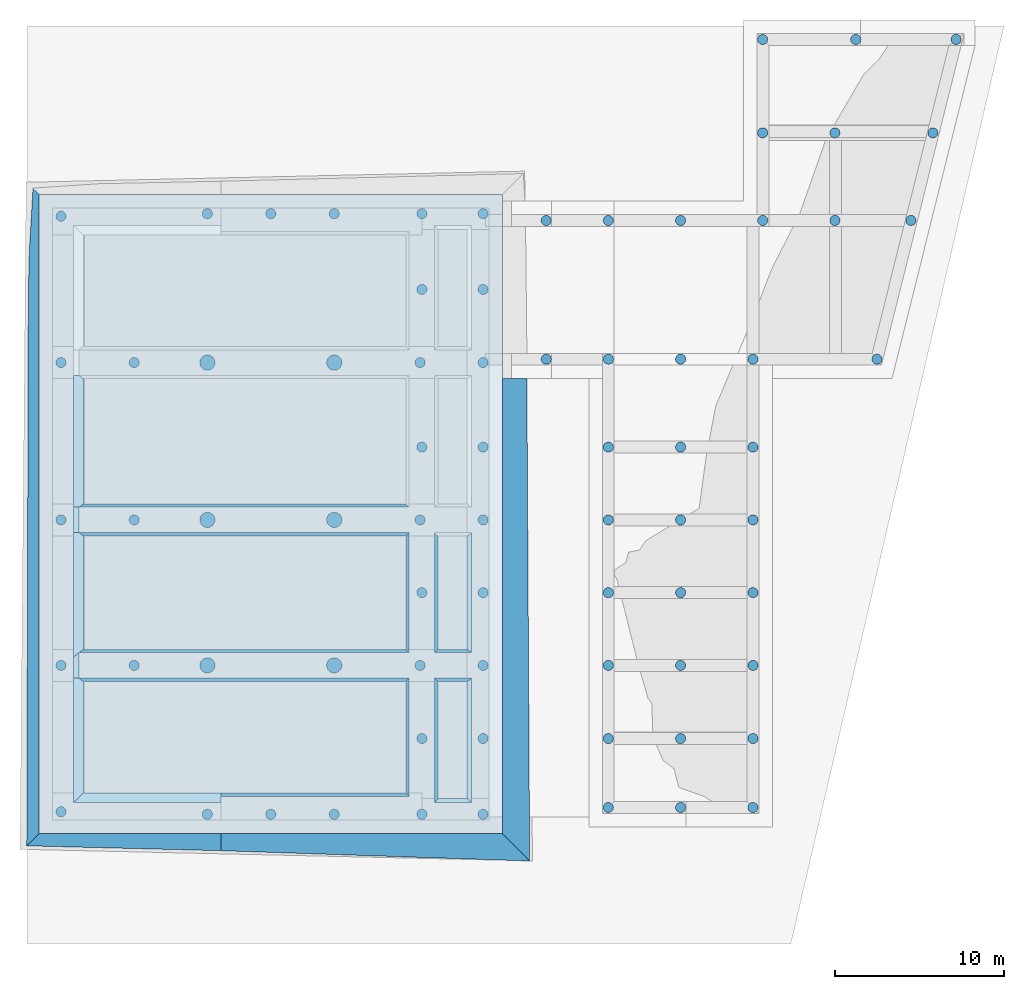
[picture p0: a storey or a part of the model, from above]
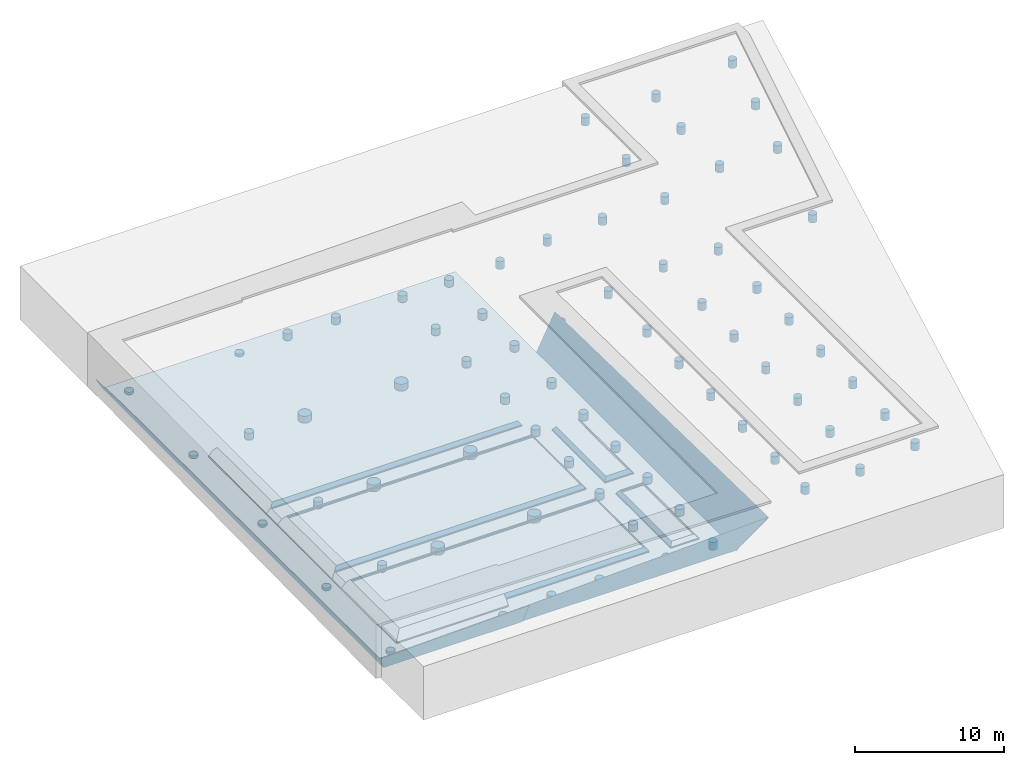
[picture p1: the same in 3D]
Properties of the parts of a building model (IFC2X3)

# File
Description: ViewDefinition [CoordinationView_V2.0, QuantityTakeOffAddOnView, SpaceBoundary2ndLevelAddOnView], Option [Elements to export: Entire project], Option [Partial Structure Display: Entire Model], Option [IFC Domain: All], Option [Structural Function: All Elements], Option [Convert Grid elements: On], Option [Convert IFC Annotations and ARCHICAD 2D elements: Off], Option [Convert 2D symbols of Doors and Windows: Off], Option [Export geometries that Participates in Collision Detection only: Off], Option [Split complex elements: Off], Option [Material Preservation: Explode where necessary], Option [Elements in Solid Element Operations: Extruded/revolved], Option [Elements with junctions: Extruded/revolved without junctions], Option [IFC Model position: Survey Point and Project Origin], Option [Curtain Wall export mode: Container Element], Option [Railing export mode: Single Element], Option [Stair export mode: Container Element], Option [Properties To Export: All properties], Option [Space containment: On], Option [IFC Domain For Space Containment: All], Option [Bounding Box: Off], Option [Geometry to type objects: Off], Option [Element Properties: Off], Option [Building Material Properties: Off], Option [Element Parameters: Off], Option [Component Parameters: Off], Option [IFC Base Quantities: On], Option [Door Window Parameters: On], Option [IFC Space boundaries: On], Option [ARCHICAD Zone Categories as IFC Space classification data: Off], Option [Element Classifications: Off]
File name: C:\Users\QGPC4\Desktop\VV Přelouč - Výkopy 3D model.ifc
Time: 2024-04-22T10:31:03
Author: Architect
Organization: Building Designer Office
Written by: The EXPRESS Data Manager Version 5.02.0100.09 : 26 Sep 2013
Made in: IFC file generated by GRAPHISOFT ARCHICAD 25.0.0 CZE FULL Windows version (IFC add-on version: 4013 CZE FULL).
Authorization: The authorising person

# IfcSite, Exteriér
RefLatitude: 50, 5, 0, 0; RefLongitude: 14, 25, 0, 0; RefElevation: 180000 mm
BaseQuantities - GrossPerimeter: 0 mm; GrossArea: 0 m2

# IfcBuilding, Budova
BaseQuantities - GrossFloorArea: 0 m2

# IfcBuildingStorey (5)
In: Budova
BaseQuantities - GrossFloorArea: 0 m2
Name | Elevation (mm) | NetHeight (mm) = GrossHeight (mm) = Height (mm)
Základy | -5000 | 1900
1.PP | -3100 | 3100
1.NP | 0 | 2950
Střecha - světlíky | 2950 | 6000
Střecha pohled | 8950 | 6000

# IfcBuildingElementProxy: Beton Prostý C 16/20 100 (36)
In: Základy
Material: Beton Prostý C 16/20
AC_Pset_RenovationAndPhasing - Renovation Status: Existing

# IfcBuildingElementProxy: Nástěnný hydrant 25, Ž01
In: 1.PP
AC_Pset_RenovationAndPhasing - Renovation Status: New

# IfcColumn: Železobeton C 20/25 D600 (67)
In: Základy
Type - PredefinedType: COLUMN
Material: Železobeton C 20/25
AC_Pset_RenovationAndPhasing - Renovation Status: Existing
Pset_ColumnCommon - LoadBearing: yes; Reference: Železobeton C 20/25 D600
BaseQuantities - Length: 650 mm; Width: 600 mm; Depth: 600 mm; CrossSectionArea: 0.282743 m2; OuterSurfaceArea: 1.22396 m2; TotalSurfaceArea: 1.78713 m2; GrossSurfaceArea: 1.78713 m2; GrossVolume: 0.183028 m3; NetVolume: 0.183028 m3

# IfcColumn: Železobeton C 20/25 D900 (6)
In: Základy
Type - PredefinedType: COLUMN
Material: Železobeton C 20/25
AC_Pset_RenovationAndPhasing - Renovation Status: Existing
Pset_ColumnCommon - LoadBearing: yes; Reference: Železobeton C 20/25 D900
BaseQuantities - Length: 650 mm; Width: 900 mm; Depth: 900 mm; CrossSectionArea: 0.636173 m2; OuterSurfaceArea: 1.83652 m2; TotalSurfaceArea: 3.10523 m2; GrossSurfaceArea: 3.10523 m2; GrossVolume: 0.412332 m3; NetVolume: 0.412332 m3

# IfcCovering: Zemina - původní 4395, Vytěžená zemina
In: Základy
Type - PredefinedType: CEILING
Material: Zemina - původní
Pset_CoveringCommon - Material: Zemina - původní
AC_Pset_RenovationAndPhasing - Renovation Status: Existing
BaseQuantities - GrossArea: 23.6487 m2; NetArea: 23.6487 m2

# IfcSlab: Beton Prostý C 16/20 58 (26)
In: Základy
Type - PredefinedType: ROOF
Material: Beton Prostý C 16/20 58.3966 mm
AC_Pset_RenovationAndPhasing - Renovation Status: Existing
Pset_SlabCommon - LoadBearing: yes
BaseQuantities - Width: 58.3966 mm
Name | Perimeter (mm) | GrossArea (m2) = NetArea (m2) | GrossVolume (m3) = NetVolume (m3)
6 x Podkladní beton | 4730.63 | 0.669559 | 0.0391
3 x Podkladní beton | 39400.8 | 6.60656 | 0.385801
2 x Podkladní beton | 15993.2 | 2.60289 | 0.152
2 x Podkladní beton | 15090.6 | 2.44363 | 0.1427
Podkladní beton | 14648 | 2.57975 | 0.150649
3 x Podkladní beton | 39398.9 | 6.58411 | 0.38449
2 x Podkladní beton | 22767.4 | 3.75974 | 0.219556
Podkladní beton | 4783.77 | 0.73093 | 0.0426839
2 x Podkladní beton | 14593.2 | 2.36315 | 0.138
2 x Podkladní beton | 15143.8 | 2.66761 | 0.15578
2 x Podkladní beton | 14383.2 | 2.32719 | 0.1359

# IfcSlab: Beton Prostý C 16/20 60, Podkladní beton
In: Základy
Type - PredefinedType: ROOF
Material: Beton Prostý C 16/20 60.0958 mm
AC_Pset_RenovationAndPhasing - Renovation Status: Existing
Pset_SlabCommon - LoadBearing: yes
BaseQuantities - Width: 60.0958 mm; Perimeter: 4783.77 mm; GrossArea: 0.73093 m2; NetArea: 0.73093 m2; GrossVolume: 0.0439258 m3; NetVolume: 0.0439258 m3

# IfcSlab: Beton Prostý C 16/20 67 (10)
In: Základy
Type - PredefinedType: ROOF
AC_Pset_RenovationAndPhasing - Renovation Status: Existing
Pset_SlabCommon - LoadBearing: yes
Name | Material | Width (mm) | Perimeter (mm) | GrossArea (m2) = NetArea (m2) | GrossVolume (m3) = NetVolume (m3)
2 x Podkladní beton | Beton Prostý C 16/20 66.8834 mm | 66.8834 | 15866.2 | 5.94135 | 0.397378
2 x Podkladní beton | Beton Prostý C 16/20 66.8834 mm | 66.8834 | 3941.6 | 0.706203 | 0.0472333
Podkladní beton | Beton Prostý C 16/20 66.8669 mm | 66.8669 | 16048 | 2.84146 | 0.19
2 x Podkladní beton | Beton Prostý C 16/20 66.8834 mm | 66.8834 | 18725.5 | 7.12317 | 0.476422
Podkladní beton | Beton Prostý C 16/20 66.8834 mm | 66.8834 | 16989.8 | 6.51429 | 0.435698
Podkladní beton | Beton Prostý C 16/20 66.8834 mm | 66.8834 | 3752.91 | 0.64693 | 0.0432689
Podkladní beton | Beton Prostý C 16/20 66.8834 mm | 66.8834 | 15904.7 | 5.98224 | 0.400112

# IfcSlab: Hutněný násyp 150, Zásyp
In: 1.PP
Type - PredefinedType: FLOOR
Material: Hutněný násyp 150 mm
AC_Pset_RenovationAndPhasing - Renovation Status: Existing
Pset_SlabCommon - LoadBearing: yes
BaseQuantities - Width: 150 mm; Perimeter: 123480 mm; GrossArea: 0 m2; NetArea: 0 m2; GrossVolume: 0 m3; NetVolume: 0 m3

# IfcSlab: Hutněný násyp 1631, Zásyp
In: Základy
Type - PredefinedType: FLOOR
Material: Hutněný násyp 1631.38 mm
AC_Pset_RenovationAndPhasing - Renovation Status: Existing
Pset_SlabCommon - LoadBearing: yes
BaseQuantities - Width: 1631.38 mm; Perimeter: 83320 mm; GrossArea: 180.492 m2; NetArea: 180.492 m2; GrossVolume: 216.451 m3; NetVolume: 216.451 m3

# IfcSlab: Hutněný násyp 3590, Zásyp
In: Základy
Type - PredefinedType: FLOOR
Material: Hutněný násyp 3590 mm
AC_Pset_RenovationAndPhasing - Renovation Status: Existing
Pset_SlabCommon - LoadBearing: yes
BaseQuantities - Width: 3590 mm; Perimeter: 45535.8 mm; GrossArea: 114.391 m2; NetArea: 114.146 m2; GrossVolume: 411.399 m3; NetVolume: 410.517 m3

# IfcSlab: Hutněný násyp 4421, Zásyp
In: Základy
Type - PredefinedType: FLOOR
Material: Hutněný násyp 4421.18 mm
AC_Pset_RenovationAndPhasing - Renovation Status: Existing
Pset_SlabCommon - LoadBearing: yes
BaseQuantities - Width: 4421.18 mm; Perimeter: 263091 mm; GrossArea: 0 m2; NetArea: 0 m2; GrossVolume: 476.972 m3; NetVolume: 476.972 m3

# IfcSlab: Hutněný násyp 700 (11)
In: Základy
Type - PredefinedType: FLOOR
Material: Hutněný násyp 700 mm
AC_Pset_RenovationAndPhasing - Renovation Status: Existing
Pset_SlabCommon - LoadBearing: yes
BaseQuantities - Width: 700 mm
Name | Perimeter (mm) | GrossArea (m2) | NetArea (m2) | GrossVolume (m3) | NetVolume (m3)
Zásyp | 22500 | 12.4814 | 12.2852 | 2.25481 | 2.11744
Zásyp | 22900 | 7.29258 | 7.29258 | 0.57054 | 0.57054
Zásyp | 29727.8 | 25.4487 | 25.1651 | 5.4664 | 5.26789
Zásyp | 26654.7 | 15.9011 | 11.262 | 4.54066 | 1.29328
Zásyp | 22900 | 4.10036 | 4.10036 | 0.343008 | 0.343008
Zásyp | 24700 | 27.8245 | 27.8245 | 7.25127 | 7.25127
Zásyp | 20752.4 | 0 | 0 | 0 | 0
Zásyp | 30700 | 58.5365 | 58.5365 | 23.9905 | 23.9905
Zásyp | 22900 | 18.6996 | 18.6996 | 4.39526 | 4.39526
Zásyp | 23340 | 4.26716 | 4.26716 | 0.286414 | 0.286414
Zásyp | 22900 | 3.23502 | 3.23502 | 0.0932595 | 0.0932595

# IfcSlab: Hutněný násyp 728 (5)
In: Základy
Type - PredefinedType: FLOOR
Material: Hutněný násyp 728 mm
AC_Pset_RenovationAndPhasing - Renovation Status: Existing
Pset_SlabCommon - LoadBearing: yes
BaseQuantities - Width: 728 mm; NetArea: 0 m2
Name | Perimeter (mm) | GrossArea (m2) | GrossVolume (m3) | NetVolume (m3)
Zásyp | 19080 | 0 | 2.01844 | 2.01844
Zásyp | 19960 | 0 | 2.04646 | 2.04646
Zásyp | 223142 | 2.33127 | 27.8688 | 26.1716
Zásyp | 18560 | 0.391 | 2.23802 | 1.95337
Zásyp | 19080 | 0 | 2.01968 | 2.01968

# IfcSlab: Zemina - původní 0, Pomocné výkopy
In: Základy
Type - PredefinedType: ROOF
Material: Zemina - původní 0.45399 mm
AC_Pset_RenovationAndPhasing - Renovation Status: Existing
Pset_SlabCommon - LoadBearing: yes
BaseQuantities - Width: 0.45399 mm; Perimeter: 41026.9 mm; GrossArea: 49.7158 m2; NetArea: 49.7158 m2; GrossVolume: 0.0225705 m3; NetVolume: 0.0225705 m3

# IfcSlab: Zemina - původní 1 (32)
Type - PredefinedType: FLOOR
Material: Zemina - původní 1 mm
AC_Pset_RenovationAndPhasing - Renovation Status: Existing
Pset_SlabCommon - LoadBearing: yes
BaseQuantities - Width: 1 mm
Name | In | Perimeter (mm) | GrossArea (m2) | NetArea (m2) | GrossVolume (m3) | NetVolume (m3)
Pomocné výkopy | Základy | 22450 | 0 | 0 | 0 | 0
Pomocné výkopy | Základy | 16400 | 5.24999 | 5.24999 | 0.00524999 | 0.00524999
Pomocné výkopy | Základy | 41628.3 | 14.0722 | 13.7878 | 0.0140722 | 0.0137878
6 x Pomocné výkopy | Základy | 17100 | 5.495 | 5.21342 | 0.005495 | 0.00521342
Pomocné výkopy | Základy | 64806.1 | 46.3541 | 44.6646 | 0.0463541 | 0.0446646
Pomocné výkopy | Základy | 53528.7 | 37.8954 | 36.4886 | 0.0378954 | 0.0364886
3 x Pomocné výkopy | Základy | 22900 | 28.26 | 28.26 | 0.02826 | 0.02826
Pomocné výkopy | Základy | 9040.01 | 4.53002 | 4.53002 | 0.00453002 | 0.00453002
Pomocné výkopy | Základy | 10440 | 5.58 | 5.29842 | 0.00558 | 0.00529842
Pomocné výkopy | Základy | 7710.39 | 3.5328 | 3.25121 | 0.0035328 | 0.00325121
Pomocné výkopy | Základy | 29727.8 | 47.6959 | 47.4123 | 0.0476959 | 0.0474123
Pomocné výkopy | Základy | 7710.38 | 3.53278 | 3.2512 | 0.00353278 | 0.0032512
Pomocné výkopy | Základy | 67500 | 47.175 | 45.2039 | 0.047175 | 0.0452039
Pomocné výkopy | Základy | 23340 | 31.2749 | 31.2749 | 0.0312749 | 0.0312749
Pomocné výkopy | Základy | 130405 | 1035.82 | 1023 | 1.03582 | 1.023
Pomocné výkopy | Základy | 16529.1 | 10.1468 | 9.86525 | 0.0101468 | 0.00986525
Pomocné výkopy | Základy | 24700 | 35.3251 | 35.3251 | 0.0353251 | 0.0353251
Pomocné výkopy | Základy | 18114.7 | 20.1917 | 19.3445 | 0.0201917 | 0.0193445
Pomocné výkopy | Základy | 20752.4 | 20.7112 | 20.7112 | 0.0207112 | 0.0207112
Pomocné výkopy | Základy | 20145.5 | 6.55342 | 6.2746 | 0.00655342 | 0.0062746
Pomocné výkopy | Základy | 16240.1 | 16.2437 | 15.6366 | 0.0162437 | 0.0156366
Pomocné výkopy | Základy | 22950 | 28.4563 | 28.4563 | 0.0284563 | 0.0284563
Pomocné výkopy | Základy | 58065.3 | 40.0433 | 39.1986 | 0.0400433 | 0.0391986
Pomocné výkopy | Základy | 41455.5 | 99.2071 | 99.2071 | 0.0992071 | 0.0992071
Pomocné výkopy | 1.PP | 1894.92 | 0.117967 | 0.0147459 | 0.000117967 | 0.0000147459

# IfcSlab: Zemina - původní 15 (7)
In: Základy
Type - PredefinedType: ROOF
Material: Zemina - původní 14.9817 mm
AC_Pset_RenovationAndPhasing - Renovation Status: Existing
Pset_SlabCommon - LoadBearing: yes
BaseQuantities - Width: 14.9817 mm
Name | Perimeter (mm) | GrossArea (m2) = NetArea (m2) | GrossVolume (m3) = NetVolume (m3)
Pomocné výkopy | 7916.47 | 2.90696 | 0.0435512
2 x Pomocné výkopy | 5311.99 | 1.73399 | 0.0259782
Pomocné výkopy | 62459.5 | 92.5506 | 1.38656
Pomocné výkopy | 24544.4 | 15.1893 | 0.227561
Pomocné výkopy | 21165.8 | 23.1113 | 0.346246
Pomocné výkopy | 39229.2 | 37.6348 | 0.563833

# IfcSlab: Zemina - původní 20 (2)
In: Základy
Type - PredefinedType: ROOF
Material: Zemina - původní 19.8599 mm
AC_Pset_RenovationAndPhasing - Renovation Status: Existing
Pset_SlabCommon - LoadBearing: yes
BaseQuantities - Width: 19.8599 mm
Name | Perimeter (mm) | GrossArea (m2) = NetArea (m2) | GrossVolume (m3) = NetVolume (m3)
Pomocné výkopy | 26233.1 | 21.2069 | 0.421167
Pomocné výkopy | 79380.1 | 55.4972 | 1.10217

# IfcSlab: Základová deska 1.NP 208, D056
In: 1.PP
Type - PredefinedType: FLOOR
Material: 2x SBS asfaltový pás, AL vložka (HI, radon) 8 mm, Železobeton C 20/25 200 mm
AC_Pset_RenovationAndPhasing - Renovation Status: Existing
Pset_SlabCommon - LoadBearing: yes
BaseQuantities - Width: 208 mm; Perimeter: 144473 mm; GrossArea: 579.784 m2; NetArea: 579.784 m2; GrossVolume: 120.595 m3; NetVolume: 120.595 m3

# IfcSlab: Základová deska garáž 308, D055
In: 1.PP
Type - PredefinedType: FLOOR
Material: 2x SBS asfaltový pás, AL vložka (HI, radon) 8 mm, Železobeton C 20/25 300 mm
AC_Pset_RenovationAndPhasing - Renovation Status: Existing
Pset_SlabCommon - LoadBearing: yes
BaseQuantities - Width: 308 mm; Perimeter: 124000 mm; GrossArea: 933.96 m2; NetArea: 933.68 m2; GrossVolume: 287.744 m3; NetVolume: 287.658 m3

# IfcWall: Betonový základ bližší boky 1605 x 628 (2)
In: Základy
Material: Železobeton C 20/25
AC_Pset_RenovationAndPhasing - Renovation Status: Existing
Pset_WallCommon - LoadBearing: yes
BaseQuantities - Length: 9057.25 mm; Height: 628 mm; Width: 1605 mm; GrossFootprintArea: 10.3633 m2; NetFootprintArea: 10.3633 m2; GrossSideArea: 7.33781 m2; NetSideArea: 7.33781 m2; GrossVolume: 8.27602 m3; NetVolume: 8.27602 m3

# IfcWall: Betonový základ předek 1815 x 628, ST28
In: Základy
Material: Železobeton C 20/25
AC_Pset_RenovationAndPhasing - Renovation Status: Existing
Pset_WallCommon - LoadBearing: yes
BaseQuantities - Length: 34595 mm; Height: 628 mm; Width: 1815 mm; GrossFootprintArea: 42.65 m2; NetFootprintArea: 42.65 m2; GrossSideArea: 24.7091 m2; NetSideArea: 24.7091 m2; GrossVolume: 32.2603 m3; NetVolume: 32.2603 m3

# IfcWall: Betonový základ vnitřní 1900 x 278 (4)
In: Základy
Material: Železobeton C 20/25
AC_Pset_RenovationAndPhasing - Renovation Status: Existing
Pset_WallCommon - LoadBearing: yes
BaseQuantities - Height: 278 mm; Width: 1900 mm
Name | Length (mm) | GrossFootprintArea (m2) = NetFootprintArea (m2) | GrossSideArea (m2) = NetSideArea (m2) | GrossVolume (m3) = NetVolume (m3)
3 x ST27 | 22695 | 34.7927 | 7.85794 | 10.8392
ST26 | 34595 | 45.4425 | 10.1353 | 13.9736

# IfcWall: Betonový základ vzdálenější boky 1605 x 278 (2)
In: Základy
Material: Železobeton C 20/25
AC_Pset_RenovationAndPhasing - Renovation Status: Existing
Pset_WallCommon - LoadBearing: yes
BaseQuantities - Length: 11865.3 mm; Height: 278 mm; Width: 1605 mm
Name | GrossFootprintArea (m2) = NetFootprintArea (m2) | GrossSideArea (m2) = NetSideArea (m2) | GrossVolume (m3) = NetVolume (m3)
ST22 | 15.9204 | 3.6806 | 4.70435
ST22 | 15.6169 | 3.4173 | 4.60774

# IfcWall: Betonový základ záda 1290 x 278 (3)
In: Základy
Material: Železobeton C 20/25
AC_Pset_RenovationAndPhasing - Renovation Status: Existing
Pset_WallCommon - LoadBearing: yes
BaseQuantities - Height: 278 mm; Width: 1290 mm
Name | Length (mm) | GrossFootprintArea (m2) = NetFootprintArea (m2) | GrossSideArea (m2) = NetSideArea (m2) | GrossVolume (m3) = NetVolume (m3)
ST24 | 34910 | 36.5664 | 11.4193 | 11.3453
ST23 | 2375 | 5.2208 | 1.63621 | 1.62583
ST23 | 2375 | 2.2672 | 0.63721 | 0.63056

# IfcWallStandardCase: Zemina - původní 700 (10)
In: Základy
Material: Zemina - původní 700 mm
AC_Pset_RenovationAndPhasing - Renovation Status: Existing
Pset_WallCommon - LoadBearing: yes
BaseQuantities - Height: 1 mm; Width: 700 mm; GrossFootprintArea: 0 m2; NetFootprintArea: 0 m2; GrossSideArea: 0 m2; NetSideArea: 0 m2; GrossVolume: 0 m3; NetVolume: 0 m3
Name | Length (mm)
5 x pomocné výkopy | 7850
pomocné výkopy | 12229.1
pomocné výkopy | 7499.98
pomocné výkopy | 9362.02
pomocné výkopy | 8053.44
pomocné výkopy | 10700

# IfcWallStandardCase: Železobeton C 20/25 700 (22)
In: Základy
Material: Železobeton C 20/25 700 mm
AC_Pset_RenovationAndPhasing - Renovation Status: Existing
Pset_WallCommon - LoadBearing: yes
BaseQuantities - Width: 700 mm
Name | Length (mm) | Height (mm) | GrossFootprintArea (m2) = NetFootprintArea (m2) | GrossSideArea (m2) = NetSideArea (m2) | GrossVolume (m3) = NetVolume (m3)
ST19 | 3720 | 2040 | 2.604 | 7.5888 | 5.31216
5 x ST19 | 7850 | 700 | 5.495 | 5.495 | 3.8465
ST19 | 15870.3 | 700 | 11.1167 | 11.1167 | 7.78168
ST19 | 8053.44 | 700 | 5.14741 | 5.14741 | 3.60318
2 x ST19 | 3880 | 2660 | 2.716 | 10.3208 | 7.22456
ST19 | 12580 | 700 | 8.80599 | 8.80599 | 6.16419
ST19 | 26500 | 1390 | 19.04 | 37.808 | 26.4656
ST19 | 7499.98 | 700 | 5.24999 | 5.24999 | 3.67499
ST19 | 5666.61 | 1100 | 4.28019 | 6.15995 | 4.31197
ST19 | 10350 | 1820 | 7 | 18.2 | 12.74
ST19 | 9150 | 1820 | 6.405 | 16.653 | 11.6571
ST19 | 26150 | 808 | 18.55 | 21.412 | 14.9884
ST19 | 3950 | 800 | 2.52 | 2.88 | 2.016
ST19 | 4600 | 1390 | 2.975 | 5.9075 | 4.13525
ST19 | 19478.2 | 700 | 13.6348 | 13.6348 | 9.54434
ST19 | 3020 | 2040 | 2.114 | 6.1608 | 4.31256
ST19 | 5764.56 | 1820 | 4.28019 | 11.1285 | 7.78995

# IfcWallStandardCase: Železobeton C 20/25 900, ST19
In: Základy
Material: Železobeton C 20/25 900 mm
AC_Pset_RenovationAndPhasing - Renovation Status: Existing
Pset_WallCommon - LoadBearing: yes
BaseQuantities - Length: 9344.57 mm; Height: 700 mm; Width: 900 mm; GrossFootprintArea: 8.41012 m2; NetFootprintArea: 8.41012 m2; GrossSideArea: 6.5412 m2; NetSideArea: 6.5412 m2; GrossVolume: 5.88708 m3; NetVolume: 5.88708 m3
